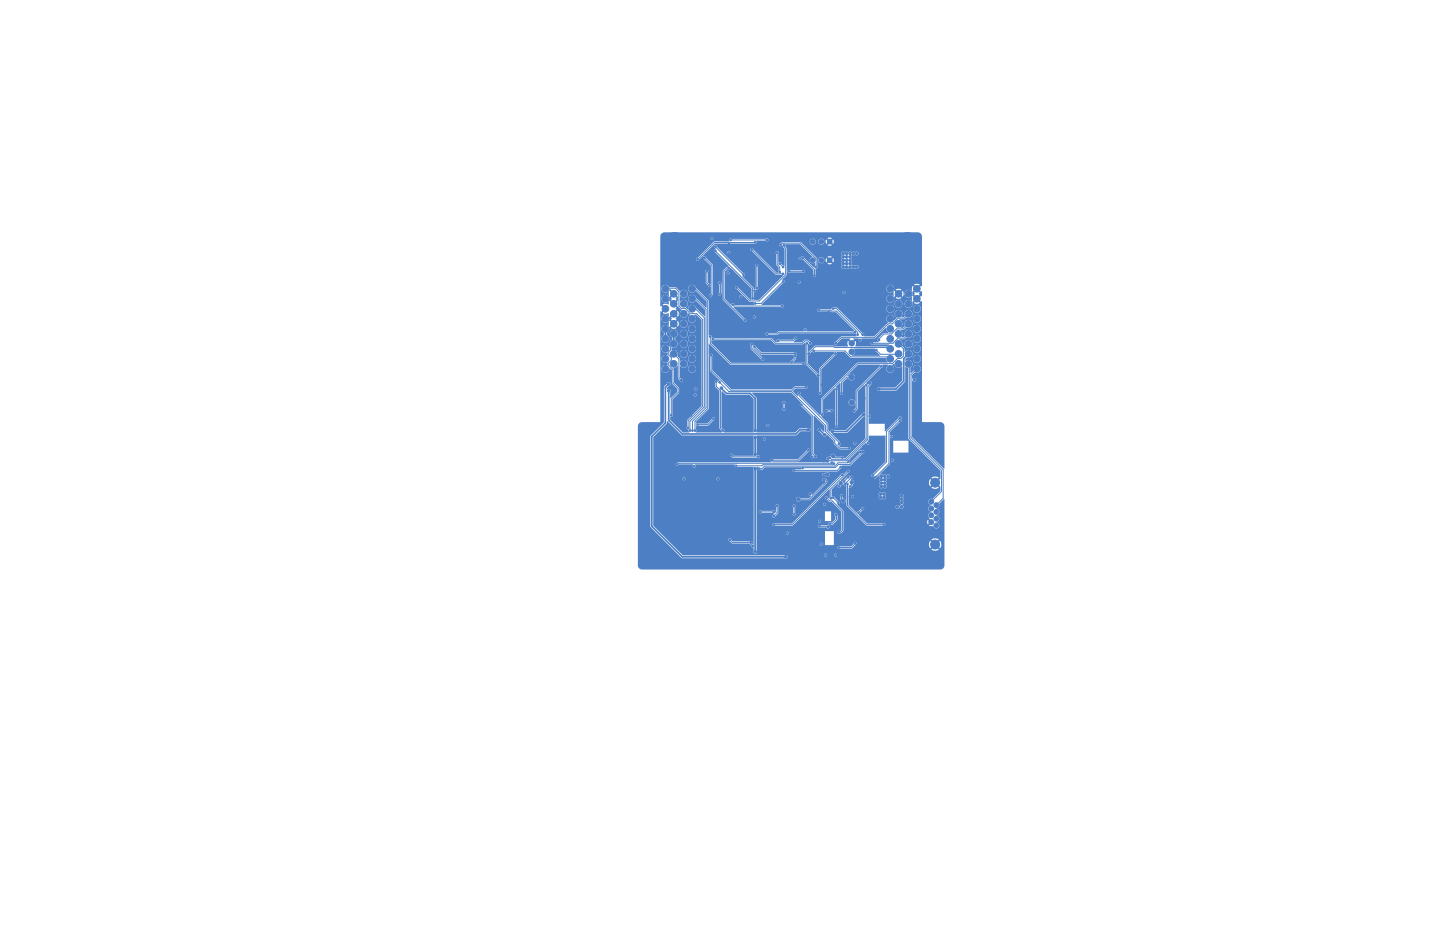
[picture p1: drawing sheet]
<svg xmlns="http://www.w3.org/2000/svg" width="432mm" height="279mm" viewBox="0 0 432 279" stroke-linecap="round" stroke-linejoin="round" font-family="sans-serif">
<g fill="#4d7fc4" stroke="#4d7fc4" stroke-width=".3">
<circle cx="255.4" cy="102.9" r=".8"/>
<circle cx="255.4" cy="105.5" r=".8"/>
<circle cx="255.4" cy="113.1" r=".8"/>
<circle cx="255.4" cy="120.7" r=".8"/>
<circle cx="202.3" cy="72.9" r="3.2"/>
<circle cx="278.5" cy="130.1" r="3.2"/>
<circle cx="196" cy="165.7" r="3.2"/>
<circle cx="207.5" cy="86.6" r="1"/>
<circle cx="207.5" cy="89.6" r="1"/>
<circle cx="207.5" cy="92.6" r="1"/>
<circle cx="207.5" cy="95.6" r="1"/>
<circle cx="207.5" cy="98.6" r="1"/>
<circle cx="207.5" cy="101.6" r="1"/>
<circle cx="207.5" cy="104.6" r="1"/>
<circle cx="207.5" cy="107.6" r="1"/>
<circle cx="207.5" cy="110.6" r="1"/>
<circle cx="205" cy="88.1" r="1"/>
<circle cx="205" cy="91.1" r="1"/>
<circle cx="205" cy="94.1" r="1"/>
<circle cx="205" cy="97.1" r="1"/>
<circle cx="205" cy="100.1" r="1"/>
<circle cx="205" cy="103.1" r="1"/>
<circle cx="205" cy="106.1" r="1"/>
<circle cx="205" cy="109.1" r="1"/>
<circle cx="202" cy="88.1" r="1"/>
<circle cx="202" cy="91.1" r="1"/>
<circle cx="202" cy="94.1" r="1"/>
<circle cx="202" cy="97.1" r="1"/>
<circle cx="202" cy="100.1" r="1"/>
<circle cx="202" cy="103.1" r="1"/>
<circle cx="202" cy="106.1" r="1"/>
<circle cx="202" cy="109.1" r="1"/>
<circle cx="199.5" cy="86.6" r="1"/>
<circle cx="199.5" cy="89.6" r="1"/>
<circle cx="199.5" cy="92.6" r="1"/>
<circle cx="199.5" cy="95.6" r="1"/>
<circle cx="199.5" cy="98.6" r="1"/>
<circle cx="199.5" cy="101.6" r="1"/>
<circle cx="199.5" cy="104.6" r="1"/>
<circle cx="199.5" cy="107.6" r="1"/>
<circle cx="199.5" cy="110.6" r="1"/>
<circle cx="243.7" cy="78" r=".72"/>
<circle cx="246.3" cy="78" r=".72"/>
<circle cx="248.8" cy="78" r=".72"/>
<circle cx="266.9" cy="110.6" r="1"/>
<circle cx="266.9" cy="107.6" r="1"/>
<circle cx="266.9" cy="104.6" r="1"/>
<circle cx="266.9" cy="101.6" r="1"/>
<circle cx="266.9" cy="98.6" r="1"/>
<circle cx="266.9" cy="95.6" r="1"/>
<circle cx="266.9" cy="92.6" r="1"/>
<circle cx="266.9" cy="89.6" r="1"/>
<circle cx="266.9" cy="86.6" r="1"/>
<circle cx="269.4" cy="109.1" r="1"/>
<circle cx="269.4" cy="106.1" r="1"/>
<circle cx="269.4" cy="103.1" r="1"/>
<circle cx="269.4" cy="100.1" r="1"/>
<circle cx="269.4" cy="97.1" r="1"/>
<circle cx="269.4" cy="94.1" r="1"/>
<circle cx="269.4" cy="91.1" r="1"/>
<circle cx="269.4" cy="88.1" r="1"/>
<circle cx="272.4" cy="109.1" r="1"/>
<circle cx="272.4" cy="106.1" r="1"/>
<circle cx="272.4" cy="103.1" r="1"/>
<circle cx="272.4" cy="100.1" r="1"/>
<circle cx="272.4" cy="97.1" r="1"/>
<circle cx="272.4" cy="94.1" r="1"/>
<circle cx="272.4" cy="91.1" r="1"/>
<circle cx="272.4" cy="88.1" r="1"/>
<circle cx="274.9" cy="110.6" r="1"/>
<circle cx="274.9" cy="107.6" r="1"/>
<circle cx="274.9" cy="104.6" r="1"/>
<circle cx="274.9" cy="101.6" r="1"/>
<circle cx="274.9" cy="98.6" r="1"/>
<circle cx="274.9" cy="95.6" r="1"/>
<circle cx="274.9" cy="92.6" r="1"/>
<circle cx="274.9" cy="89.6" r="1"/>
<circle cx="274.9" cy="86.6" r="1"/>
<circle cx="272.2" cy="72.9" r="3.2"/>
<circle cx="243.7" cy="72.4" r=".72"/>
<circle cx="246.3" cy="72.4" r=".72"/>
<circle cx="248.8" cy="72.4" r=".72"/>
<circle cx="280.8" cy="151.4" r=".72"/>
<circle cx="279.2" cy="150.4" r=".72"/>
<circle cx="279.2" cy="152.4" r=".72"/>
<circle cx="279.2" cy="154.5" r=".72"/>
<circle cx="280.8" cy="153.5" r=".72"/>
<circle cx="280.8" cy="155.5" r=".72"/>
<circle cx="280.8" cy="157.5" r=".72"/>
<circle cx="279.2" cy="156.5" r=".72"/>
<circle cx="280.4" cy="163.2" r="1.35"/>
<circle cx="280.4" cy="144.7" r="1.35"/>
<circle cx="252.9" cy="150.2" r=".5"/>
<circle cx="252.1" cy="144.8" r=".5"/>
<circle cx="248" cy="142.3" r=".5"/>
<circle cx="255.4" cy="144.6" r=".5"/>
<circle cx="249.8" cy="136.7" r=".5"/>
<circle cx="239.4" cy="149.7" r=".5"/>
<circle cx="232" cy="158.5" r=".25"/>
<circle cx="264.8" cy="135.4" r=".25"/>
<circle cx="229.2" cy="135.4" r=".25"/>
<circle cx="219.1" cy="134.2" r=".25"/>
<circle cx="257.9" cy="88.9" r=".25"/>
<circle cx="218.6" cy="73.3" r=".25"/>
<circle cx="233.8" cy="88.9" r=".25"/>
<circle cx="220.1" cy="78.3" r=".25"/>
<circle cx="263" cy="74.5" r=".38"/>
<circle cx="214.2" cy="141.5" r=".25"/>
<circle cx="253.6" cy="161.6" r=".25"/>
<circle cx="251.6" cy="100.6" r=".25"/>
<circle cx="214.5" cy="77.8" r=".25"/>
<circle cx="264" cy="72.4" r=".38"/>
<circle cx="263" cy="71.4" r=".38"/>
<circle cx="217.8" cy="129.1" r=".25"/>
<circle cx="243.2" cy="98.9" r=".25"/>
<circle cx="263" cy="73.5" r=".38"/>
<circle cx="261" cy="84.1" r=".25"/>
<circle cx="207.4" cy="140.3" r=".25"/>
<circle cx="240.7" cy="145.6" r=".25"/>
<circle cx="217.8" cy="125.5" r=".25"/>
<circle cx="251.6" cy="128.3" r=".25"/>
<circle cx="229.2" cy="94.8" r=".25"/>
<circle cx="264.8" cy="151.9" r=".38"/>
<circle cx="264" cy="71.4" r=".38"/>
<circle cx="224.4" cy="125.5" r=".25"/>
<circle cx="252.3" cy="97.8" r=".25"/>
<circle cx="270.6" cy="81.6" r=".38"/>
<circle cx="271.4" cy="79.8" r=".38"/>
<circle cx="224.4" cy="120.4" r=".25"/>
<circle cx="265" cy="71.4" r=".38"/>
<circle cx="269.4" cy="128.1" r=".25"/>
<circle cx="265.8" cy="151.9" r=".38"/>
<circle cx="247" cy="144.6" r=".25"/>
<circle cx="254.1" cy="133.7" r=".25"/>
<circle cx="245.7" cy="152.2" r=".25"/>
<circle cx="269.9" cy="156.3" r=".25"/>
<circle cx="269.6" cy="81.6" r=".38"/>
<circle cx="265" cy="72.4" r=".38"/>
<circle cx="259.1" cy="119.4" r=".3"/>
<circle cx="242.9" cy="87.7" r=".3"/>
<circle cx="265" cy="133.1" r=".25"/>
<circle cx="257.9" cy="113.3" r=".25"/>
<circle cx="208.2" cy="133.1" r=".25"/>
<circle cx="214" cy="91.5" r=".25"/>
<circle cx="231" cy="83.6" r=".25"/>
<circle cx="227.5" cy="146.1" r=".25"/>
<circle cx="270.9" cy="144.6" r=".38"/>
<circle cx="213" cy="111.8" r=".25"/>
<circle cx="246" cy="109" r=".25"/>
<circle cx="219.1" cy="137.7" r=".25"/>
<circle cx="271.4" cy="80.8" r=".38"/>
<circle cx="206.4" cy="143.6" r=".25"/>
<circle cx="216.8" cy="108.5" r=".25"/>
<circle cx="270.6" cy="78.5" r=".38"/>
<circle cx="235.1" cy="114.9" r=".25"/>
<circle cx="246.3" cy="161.3" r=".25"/>
<circle cx="273.2" cy="136.7" r=".25"/>
<circle cx="245.7" cy="120.7" r=".25"/>
<circle cx="207.1" cy="124.5" r=".25"/>
<circle cx="257.9" cy="96.1" r=".25"/>
<circle cx="260" cy="97.3" r=".25"/>
<circle cx="254.6" cy="165.4" r=".25"/>
<circle cx="247" cy="164.4" r=".25"/>
<circle cx="242.7" cy="166.4" r=".25"/>
<circle cx="231" cy="118.4" r=".25"/>
<circle cx="207.6" cy="161.6" r=".25"/>
<circle cx="249.3" cy="151.2" r=".25"/>
<circle cx="269.6" cy="78.5" r=".38"/>
<circle cx="206.1" cy="80.3" r=".25"/>
<circle cx="235.3" cy="96.8" r=".25"/>
<circle cx="236.1" cy="154.7" r=".25"/>
<circle cx="233" cy="124.8" r=".25"/>
<circle cx="250.1" cy="108.3" r=".25"/>
<circle cx="224.4" cy="123" r=".25"/>
<circle cx="253.1" cy="89.7" r=".25"/>
<circle cx="233" cy="104.2" r=".25"/>
<circle cx="210.2" cy="143.6" r=".25"/>
<circle cx="270.9" cy="143.3" r=".38"/>
<circle cx="267.3" cy="124.3" r=".25"/>
<circle cx="252.9" cy="165.4" r=".25"/>
<circle cx="221.1" cy="105.2" r=".25"/>
<circle cx="269.9" cy="144.6" r=".38"/>
<circle cx="233.3" cy="107.2" r=".25"/>
<circle cx="213" cy="116.9" r=".25"/>
<circle cx="269.9" cy="143.3" r=".38"/>
<circle cx="246.5" cy="115.4" r=".25"/>
<circle cx="254.9" cy="148.9" r=".25"/>
<circle cx="239.9" cy="123.2" r=".25"/>
<circle cx="219.8" cy="95.3" r=".25"/>
<circle cx="240.2" cy="131.4" r=".25"/>
<circle cx="211.5" cy="161.6" r=".25"/>
<circle cx="250.8" cy="113.6" r=".25"/>
<circle cx="250.1" cy="125.8" r=".25"/>
<circle cx="242.7" cy="127.8" r=".25"/>
<circle cx="265.8" cy="150.9" r=".38"/>
<circle cx="262.8" cy="158.3" r=".25"/>
<circle cx="246" cy="101.9" r=".25"/>
<circle cx="245.7" cy="133.1" r=".25"/>
<circle cx="217.8" cy="127.6" r=".25"/>
<circle cx="257.9" cy="104.9" r=".25"/>
<circle cx="203.1" cy="135.7" r=".25"/>
<circle cx="229" cy="107" r=".25"/>
<circle cx="220.9" cy="85.1" r=".25"/>
<circle cx="242.2" cy="96.3" r=".25"/>
<circle cx="230" cy="76.5" r=".25"/>
<circle cx="263" cy="72.4" r=".38"/>
<circle cx="269.9" cy="160.1" r=".25"/>
<circle cx="229.7" cy="124.8" r=".25"/>
<circle cx="208.2" cy="119.4" r=".25"/>
<circle cx="247" cy="138.2" r=".25"/>
<circle cx="266.8" cy="151.9" r=".38"/>
<circle cx="230.5" cy="86.4" r=".25"/>
<circle cx="248.1" cy="138.3" r=".25"/>
<circle cx="240.2" cy="75.2" r=".25"/>
<circle cx="248.5" cy="93.6" r=".25"/>
<circle cx="247.3" cy="122.5" r=".25"/>
<circle cx="264.8" cy="150.9" r=".38"/>
<circle cx="219.8" cy="98.3" r=".25"/>
<circle cx="212.7" cy="143.6" r=".25"/>
<circle cx="241.7" cy="157.5" r=".25"/>
<circle cx="262.3" cy="124.5" r=".25"/>
<circle cx="253.1" cy="128.3" r=".25"/>
<circle cx="268.9" cy="143.3" r=".38"/>
<circle cx="259" cy="128.8" r=".3"/>
<circle cx="264" cy="153.2" r=".25"/>
<circle cx="201.8" cy="142.3" r=".25"/>
<circle cx="259.5" cy="137.7" r=".25"/>
<circle cx="209.4" cy="140" r=".25"/>
<circle cx="235.8" cy="145.6" r=".25"/>
<circle cx="238.4" cy="127.3" r=".25"/>
<circle cx="258.2" cy="146.4" r=".25"/>
<circle cx="241.2" cy="165.1" r=".38"/>
<circle cx="217.8" cy="71.9" r=".25"/>
<circle cx="259" cy="133.9" r=".25"/>
<circle cx="256.3" cy="132.9" r=".25"/>
<circle cx="247.5" cy="166.4" r=".25"/>
<circle cx="257.9" cy="135.4" r=".25"/>
<circle cx="243.6" cy="137" r=".25"/>
<circle cx="265.3" cy="143.8" r=".38"/>
<circle cx="267.6" cy="138" r=".25"/>
<circle cx="242.9" cy="148.1" r=".25"/>
<circle cx="264.3" cy="144.8" r=".38"/>
<circle cx="260.2" cy="132.9" r=".25"/>
<circle cx="236.1" cy="159.8" r=".25"/>
<circle cx="265.3" cy="144.8" r=".38"/>
<circle cx="246.3" cy="163.1" r=".25"/>
<circle cx="255.6" cy="148.9" r=".25"/>
<circle cx="247.3" cy="151.2" r=".25"/>
<circle cx="264.3" cy="145.8" r=".38"/>
<circle cx="265.3" cy="142.8" r=".38"/>
<circle cx="250.6" cy="166.4" r=".25"/>
<circle cx="264.3" cy="142.8" r=".38"/>
<circle cx="205.1" cy="143.6" r=".25"/>
<circle cx="245.7" cy="156.3" r=".25"/>
<circle cx="266.3" cy="142.8" r=".38"/>
<circle cx="264.3" cy="143.8" r=".38"/>
<circle cx="265.3" cy="145.8" r=".38"/>
<circle cx="253.9" cy="79" r=".38"/>
<circle cx="252.9" cy="78" r=".38"/>
<circle cx="208.2" cy="139.7" r=".25"/>
<circle cx="267.3" cy="130.9" r=".25"/>
<circle cx="229.2" cy="131.6" r=".25"/>
<circle cx="218.6" cy="75.7" r=".25"/>
<circle cx="252.9" cy="79" r=".38"/>
<circle cx="252.9" cy="77" r=".38"/>
<circle cx="270.4" cy="151.9" r=".38"/>
<circle cx="226.2" cy="87.2" r=".25"/>
<circle cx="256.9" cy="76" r=".38"/>
<circle cx="241.4" cy="98.9" r=".25"/>
<circle cx="253.9" cy="80.1" r=".38"/>
<circle cx="253.1" cy="87.7" r=".25"/>
<circle cx="230.2" cy="127.6" r=".25"/>
<circle cx="264" cy="148.1" r=".38"/>
<circle cx="265" cy="148.1" r=".38"/>
<circle cx="253.9" cy="77" r=".38"/>
<circle cx="253.9" cy="78" r=".38"/>
<circle cx="253.9" cy="76" r=".38"/>
<circle cx="239.9" cy="77.5" r=".25"/>
<circle cx="226.2" cy="95" r=".25"/>
<circle cx="208.4" cy="118.4" r=".25"/>
<circle cx="252.9" cy="76" r=".38"/>
<circle cx="255.9" cy="76" r=".38"/>
<circle cx="255.9" cy="80.1" r=".38"/>
<circle cx="265" cy="149.1" r=".38"/>
<circle cx="256.9" cy="80.1" r=".38"/>
<circle cx="213.5" cy="71.4" r=".25"/>
<circle cx="269.1" cy="151.9" r=".38"/>
<circle cx="264" cy="149.1" r=".38"/>
<circle cx="254.9" cy="79" r=".38"/>
<circle cx="270.4" cy="150.7" r=".38"/>
<circle cx="208.7" cy="116.6" r=".25"/>
<circle cx="254.9" cy="80.1" r=".38"/>
<circle cx="222.1" cy="88.9" r=".25"/>
<circle cx="254.9" cy="76" r=".38"/>
<circle cx="270.4" cy="148.6" r=".38"/>
<circle cx="254.9" cy="78" r=".38"/>
<circle cx="257.9" cy="101.9" r=".25"/>
<circle cx="270.4" cy="149.7" r=".38"/>
<circle cx="252.9" cy="80.1" r=".38"/>
<circle cx="260.8" cy="124.8" r=".25"/>
<circle cx="215.3" cy="143.6" r=".25"/>
<circle cx="239.6" cy="84.6" r=".25"/>
<circle cx="218.3" cy="81.8" r=".25"/>
<circle cx="254.9" cy="77" r=".38"/>
<circle cx="219.7" cy="91.3" r=".25"/>
<circle cx="234.6" cy="91.7" r=".25"/>
<circle cx="226.4" cy="140.5" r=".38"/>
<circle cx="226.4" cy="129.1" r=".38"/>
<circle cx="216.3" cy="116.4" r=".38"/>
<circle cx="226.4" cy="131.1" r=".38"/>
<circle cx="274.2" cy="113.8" r=".38"/>
<circle cx="226.4" cy="136.2" r=".38"/>
<circle cx="226.4" cy="165.4" r=".38"/>
<circle cx="215.8" cy="114.6" r=".25"/>
<circle cx="254.6" cy="134.4" r=".25"/>
<circle cx="206.9" cy="129.1" r=".25"/>
<circle cx="208.4" cy="129.1" r=".25"/>
<circle cx="207.6" cy="129.1" r=".25"/>
<circle cx="201.3" cy="124.5" r=".25"/>
<circle cx="239.6" cy="117.9" r=".25"/>
<circle cx="251.6" cy="133.1" r=".25"/>
<circle cx="246.5" cy="124.3" r=".25"/>
<circle cx="263.5" cy="101.9" r=".3"/>
<circle cx="258.7" cy="135.4" r=".3"/>
<circle cx="240.6" cy="140.3" r=".25"/>
<circle cx="256.2" cy="123.2" r=".25"/>
<circle cx="264.3" cy="109.8" r=".25"/>
<circle cx="261.5" cy="102.9" r=".25"/>
<circle cx="265" cy="157.3" r=".25"/>
<circle cx="254.1" cy="145.1" r=".25"/>
<circle cx="250.6" cy="106" r=".25"/>
<circle cx="250.6" cy="102.9" r=".25"/>
<circle cx="245.9" cy="117.9" r=".25"/>
<circle cx="223.4" cy="96.1" r=".25"/>
<circle cx="218.6" cy="80.3" r=".25"/>
<circle cx="226.2" cy="103.9" r=".25"/>
<circle cx="242.5" cy="106" r=".25"/>
<circle cx="238.4" cy="106" r=".25"/>
<circle cx="250.8" cy="127.8" r=".25"/>
<circle cx="250.8" cy="116.6" r=".25"/>
<circle cx="238.1" cy="141" r=".25"/>
<circle cx="252.1" cy="140" r=".25"/>
<circle cx="233" cy="151.6" r=".25"/>
<circle cx="232" cy="154.7" r=".25"/>
<circle cx="249.6" cy="129.3" r=".38"/>
<circle cx="242.4" cy="128.8" r=".38"/>
<circle cx="247.3" cy="130.4" r=".38"/>
<circle cx="245.7" cy="128.8" r=".38"/>
<circle cx="259" cy="124.3" r=".38"/>
<circle cx="200.5" cy="117.1" r=".38"/>
<circle cx="252.3" cy="117.9" r=".25"/>
<circle cx="263.5" cy="116.6" r=".38"/>
<circle cx="249.5" cy="123.1" r=".25"/>
<circle cx="247.8" cy="123.2" r=".25"/>
<circle cx="204.3" cy="114.1" r=".3"/>
<circle cx="244.7" cy="80.1" r=".25"/>
<circle cx="234.1" cy="73.4" r=".25"/>
<circle cx="212.8" cy="85.6" r=".25"/>
<circle cx="212" cy="81.3" r=".25"/>
<circle cx="211.2" cy="77.3" r=".25"/>
<circle cx="213" cy="88.7" r=".25"/>
<circle cx="231.5" cy="138" r=".25"/>
<circle cx="242.5" cy="134.9" r=".25"/>
<circle cx="220.7" cy="139.6" r=".25"/>
<circle cx="250.1" cy="139" r=".25"/>
<circle cx="258.7" cy="100.3" r=".25"/>
<circle cx="240.7" cy="77.3" r=".25"/>
<circle cx="244.2" cy="82.6" r=".25"/>
<circle cx="249.8" cy="92.5" r=".25"/>
<circle cx="234.8" cy="80.1" r=".25"/>
<circle cx="233.8" cy="79" r=".25"/>
<circle cx="257.2" cy="100.3" r=".25"/>
<circle cx="236.6" cy="81.3" r=".25"/>
<circle cx="240.9" cy="81.3" r=".25"/>
<circle cx="245.5" cy="93" r=".25"/>
<circle cx="235.1" cy="73.5" r=".25"/>
<circle cx="220.9" cy="86.2" r=".25"/>
<circle cx="214.5" cy="75.2" r=".25"/>
<circle cx="225.7" cy="89.5" r=".25"/>
<circle cx="209.2" cy="77.8" r=".25"/>
<circle cx="226.4" cy="72.6" r=".25"/>
<circle cx="230" cy="71.9" r=".25"/>
<circle cx="219.1" cy="71.9" r=".25"/>
<circle cx="222.9" cy="82.3" r=".25"/>
<circle cx="214.5" cy="74" r=".25"/>
<circle cx="203.1" cy="139.2" r=".25"/>
<circle cx="249.4" cy="138.7" r=".25"/>
<circle cx="228.7" cy="107.7" r=".25"/>
<circle cx="225.4" cy="103.2" r=".25"/>
<circle cx="225.2" cy="162.6" r=".25"/>
<circle cx="218.8" cy="161.8" r=".25"/>
<circle cx="258.7" cy="152.4" r=".25"/>
<circle cx="225.7" cy="163.6" r=".25"/>
<circle cx="257.4" cy="153.7" r=".25"/>
<circle cx="232" cy="157.3" r=".25"/>
<circle cx="252.5" cy="142.3" r=".25"/>
<circle cx="247.8" cy="149.1" r=".25"/>
<circle cx="251.6" cy="159.6" r=".25"/>
<circle cx="254.4" cy="143" r=".25"/>
<circle cx="253.1" cy="144.3" r=".25"/>
<circle cx="244" cy="105.2" r=".25"/>
<circle cx="232" cy="153.5" r=".25"/>
<circle cx="228" cy="153.5" r=".25"/>
<circle cx="255.4" cy="143" r=".25"/>
<circle cx="253.4" cy="145.1" r=".25"/>
<circle cx="248.3" cy="158" r=".25"/>
<circle cx="245.7" cy="157.8" r=".25"/>
<circle cx="250.6" cy="154.3" r=".25"/>
<circle cx="248.8" cy="157" r=".25"/>
<circle cx="251.3" cy="150.7" r=".25"/>
<circle cx="249.8" cy="149.1" r=".25"/>
<circle cx="249.1" cy="149.4" r=".25"/>
<circle cx="254.4" cy="141.3" r=".25"/>
<circle cx="245.4" cy="112.6" r=".25"/>
<circle cx="238.6" cy="101.4" r=".25"/>
<circle cx="233.3" cy="102.2" r=".25"/>
<circle cx="241.9" cy="102.9" r=".25"/>
<circle cx="248.8" cy="137.2" r=".25"/>
<circle cx="259.7" cy="115.4" r=".25"/>
<circle cx="226.4" cy="91" r=".25"/>
<circle cx="234.8" cy="84.4" r=".25"/>
<circle cx="226.9" cy="86.4" r=".25"/>
<circle cx="226.9" cy="79.5" r=".25"/>
<circle cx="261" cy="114.9" r=".25"/>
<circle cx="248.1" cy="137.5" r=".25"/>
<circle cx="233.8" cy="81.5" r=".25"/>
<circle cx="233" cy="75.7" r=".25"/>
<circle cx="214.8" cy="114.3" r=".25"/>
<circle cx="216.8" cy="129.1" r=".25"/>
<circle cx="254.4" cy="138.3" r=".25"/>
<circle cx="227.7" cy="140.5" r=".25"/>
<circle cx="251.6" cy="164.1" r=".25"/>
<circle cx="256.4" cy="162.9" r=".25"/>
<circle cx="225.4" cy="74.7" r=".25"/>
<circle cx="234.8" cy="82.1" r=".25"/>
<circle cx="214" cy="125.5" r=".25"/>
<circle cx="209.2" cy="127.3" r=".25"/>
<circle cx="230" cy="100.1" r=".25"/>
<circle cx="256.4" cy="99.6" r=".25"/>
<circle cx="262.8" cy="104.9" r=".25"/>
<circle cx="240.3" cy="121.3" r=".25"/>
<circle cx="244.5" cy="136.9" r=".25"/>
<circle cx="235.1" cy="122.7" r=".25"/>
<circle cx="235.1" cy="120.7" r=".25"/>
<circle cx="261.7" cy="142.5" r=".25"/>
<circle cx="269.9" cy="125.3" r=".25"/>
<circle cx="262.5" cy="143" r=".25"/>
<circle cx="269.9" cy="126.1" r=".25"/>
<circle cx="240.9" cy="109" r=".25"/>
<circle cx="213" cy="100.9" r=".25"/>
<circle cx="213.2" cy="106.5" r=".25"/>
<circle cx="241.7" cy="116.1" r=".25"/>
<circle cx="242.9" cy="102.9" r=".25"/>
<circle cx="213.7" cy="101.6" r=".25"/>
<circle cx="215.8" cy="88.2" r=".25"/>
<circle cx="215.8" cy="84.8" r=".25"/>
<circle cx="238.1" cy="154.2" r=".25"/>
<circle cx="238.1" cy="151.7" r=".25"/>
<circle cx="200.5" cy="115.1" r=".38"/>
<circle cx="235.6" cy="166.9" r=".38"/>
<circle cx="227.5" cy="137" r=".25"/>
<circle cx="219.3" cy="136.4" r=".25"/>
<circle cx="206.3" cy="128.3" r=".25"/>
<circle cx="251.6" cy="145.8" r=".25"/>
<circle cx="252.3" cy="148.6" r=".25"/>
<circle cx="254.9" cy="145.8" r=".25"/>
<circle cx="247" cy="142.3" r=".25"/>
<circle cx="247" cy="143.8" r=".3"/>
<circle cx="252.6" cy="137.1" r=".25"/>
<circle cx="238.4" cy="106.7" r=".25"/>
<circle cx="237.4" cy="108.5" r=".25"/>
</g>
<g fill="none" stroke="#4d7fc4" stroke-width=".3">
<path d="M211.2 77.3l2.3 2.3v8.6l-.5 .5M214.5 75.2l11.2 11.2v3.1M214.5 74l8.4 8.3M219.1 71.9h10.9M225.4 74.7l7.3 7.4h2.1M226.4 72.6l-12.2 .1-5 5.1M226.9 79.6v6.8M233 75.7v3.6l.8 .8v1.4M233.8 79l1 1.1M234.1 73.4l.5-.5h5.4l4.7 4.7v2.4M235.1 73.5v.5l.5 .5v7.8l-7.9 7.9h-2.8l-4-4M240.7 77.3l3.5 3.5v1.8"/>
<path d="M199.7 86.4h2.9l1 1v4.3l.7 .8h1.2l1.5 1.5h1.9l1.8 1.8v25.9l-4.4 4.4v2.2M207.5 92.6h1l2.7 2.6v26.8l-4.3 4.3v2.8M207.5 86.6h1l3.7 3.6v32.3l-3.8 3.8v2.8M207.5 89.6h1l3.2 3.1v29.5l-4.1 4.1v2.8M212 81.3v3.5l.8 .8M212.8 85.6h.1M215.8 84.8l.2 .3v2.8l-.2 .3M218.6 80.3h-.5l-1.1 1v8.4l6.4 6.4M219.7 91.3l.4 .4h14.5M234.8 84.4l-6.6 6.6h-1.8M236.6 81.3h4.3M244.7 80v.1"/>
<path d="M245.5 93h3.6l.2 .3h1.5l6.4 6.3v.7M249.8 92.5h1.1l7.8 7.8M256.4 99.6h-22.8l-.6 .5h-3M257.9 99.6h.1M272.4 97.1l-1.5 1.5h-2.1l-1.5 1.5h-2.3l-1.5 1.5v.3M272.4 94.1l-1.3 1.3h-1.8l-1.7 1.7h-1.3l-4 4h-10l-1.7 1.8M202 103.1l-1 1v.9l-.5 .5v.9l.8 .8v.8l-.8 .7v.8l1.3 1.3v4.1l1.5 1.5v1.3l-2 2v4.8M202 106.1l1.6 1.5v5.7l.7 .8M213 100.9v2l6.1 6.2 21.8-.1M213.2 106.5v4.5l5.9 6h18.5l.9-.9h3.2M213.7 101.6h17.6l1.2 1.3h8.1l.8-.7h.8l.7 .7M214.8 114.3v1.5l1.2 1.3v11.2l.8 .8"/>
<path d="M215.8 114.6l2.8 2.8h18.8l10.1 10.2v1.7l2.8 2.8v.8l1.5 1.5h2.8M225.4 103.2v1.2l3.3 3.3M226.2 103.9l2 2.1h10.2M238.4 106.7v.8l-1 1M238.6 101.4l-.7 .8h-4.6M239.6 117.9v.7l8.4 8.4v2.1l3.6 3.5v.5M241.9 102.9v6.2l3.5 3.5M244 105.2h9.4l1.7 1.8h11.2M250.6 106l-4.7 4.6v7.3M250.8 116.6v11.2M255.4 113.1h-1.5l-1.6 1.5v3.3M259.7 115.4v16.2l-6.1 6.1h-4.3l-.5-.5"/>
<path d="M261 114.9v.2l-.8 .8v15.8l-6.4 6.4h-5l-.7-.6M262.8 105l1.2 1.2h5.3M264.3 109.8l-7.4 7.3v5.4l-.7 .7M266.5 104.2h-16.2l-.3-.3h-5.6l-1.9 2.1M269.4 103.1l1.5 1.4v2.2l-.8 .8h-1l-1.5 1.5h-10.4l-10.7 10.7v4.6M272.4 100.1l-1.3 1.3h-1.8l-1.6 1.5h-6.2M272.7 109.3v22.1l9.6 9.6v6.3l-3.1 3.1M274.9 110.6l-1.7 1.7v18.8l9.6 9.7v8.6l-2 2M214 125.5l-1.8 1.8h-3M219.3 136.4l.5 .6h7.7M221.1 138.9h.1M235.1 120.7v2"/>
<path d="M240.3 121.3l3.4 3.5v11.3l.8 .8M242.4 134.9l-3 3.1h-7.9M242.4 134.9h.1M249.4 138.7l-.2 .2h-45.8l-.3 .3M249.5 123.1l-1.7 .1M249.8 136.7l.5 .5 2.3-.1M250.1 139l-.3 .3h-21l-.4 .3h-7.7M251.6 132.7h.1M254.4 138.3l-.3 .4h-2.8l-1 1h-21.1l-.7 .8h-.8M258.7 135.5l-3.8 3.7h-3.5l-.9 1-9.9 .1M258.7 135.4v.1M269.9 125.3l-4.1 4v9.2l-4.1 4"/>
<path d="M269.9 126.1l-3.3 3.3v9.6l-4.1 4.1M228 153.5h4M233 151.6v2.1l-1 1M238.1 151.7v2.5M245.7 157.8h2.3l.3 .2M247 142.3h1M247 143.8h.5l.3 .3v.5l-5.1 5.1h-3.3M247.8 149.1l1 1.1h.8l3 3v5.9l-.5 .5h-.5M249.8 149.1l1.5 1.6M250.6 154.3l.2 .3v1.2l-1.2 1.2h-.8M252.1 140l-1 1h-13M252.1 144.8l-.5 .5v.5"/>
<path d="M252.3 148.6v1.1l.6 .5M252.5 142.3h.1M252.5 142.3l-14.9 15h-5.6M254.1 145.1v6.3l5.9 5.9h5M254.4 143.1l-1.3 1.2M254.4 141.3l-5.3 5.2v2.9M255.4 143.1l-2 2M255.4 144.6v.7l-.5 .5M258.7 152.4l-1.3 1.3M218.8 161.8l.8 .8h5.5M225.2 162.6h-.1M225.2 162.6v.5l.5 .5"/>
<path d="M252.4 164.1h.1M252.8 164.1h.1M256.4 162.9v.2l-1.1 1h-3.7"/>
</g>
<path d="M199.5 98.9v3M200.5 115.1l-1 1v10.7l-4 4.1v26.9l9.1 9.1h31M200.5 117.1v8.9l4.1 4.1h34l1.3-1.3h2.5M202 100.1v3M216.3 116.4l1.6 1.6h7.1l1.4 1.4v9.7M272.4 106.1l-1.4 1.4v6.7l-2.4 2.4h-5.1M226.4 131.1v5.1M245.7 128.8l1.6 1.6M259 124.3l-5.1 5h-4.3M226.4 140.5v24.9" fill="none" stroke="#4d7fc4" stroke-width=".51"/>
<g fill="#4d7fc4">
<path d="M198 93.3l.3 .1 .6-.5 .4 .3-.6 .6 .7 .3 1.1-.2 .1 1a1.25 1.25 0 0 0-1.9-.2 1.25 1.25 0 0 0 .1 1.9 1.25 1.25 0 0 0 1.8-.3l-.1 1.6a1.22 1.22 0 0 0-1.9 0 1.22 1.22 0 0 0 .5 1.8v.8a1.22 1.22 0 0 0-.4 1.9 1.22 1.22 0 0 0 2-.2 1.22 1.22 0 0 0-.8-1.8l.1-.7a1.73 1.73 0 0 0 .7-1.7l.7-.6 .4 .3-.6 .6 .5 .2h4.7a1.18 1.18 0 0 0 1.6 1.2 1.18 1.18 0 0 0 .3-2 1.18 1.18 0 0 0-1.9 .7l-3.8 .1 .3-.2-.6-.6 .4-.3 .6 .5 .2-.9h.4v.2a1.18 1.18 0 0 0 1.8 .9 1.18 1.18 0 0 0 0-2 1.18 1.18 0 0 0-1.8 .9h-.4l-.2-.8-.6 .6-.4-.4 .6-.6-.3-.2 .3-.3-.6-.6 .4-.3 .6 .5a1.49 1.49 0 0 0 0-1.7l-.6 .6-.4-.4 .6-.6-.3-.2 .3-.3-.6-.6 .4-.3 1.8 1.6a1.25 1.25 0 0 0 .1 2.2 1.25 1.25 0 0 0 1.7-1.4l.7 .7a1.18 1.18 0 0 0-.4 1.8 1.18 1.18 0 0 0 1.8 .1 1.18 1.18 0 0 0-.3-1.8l.1-.3 .6 .1 1.6 1.6v25.6l-4.4 4.4-.1 2.4 .6 .4 .1 .9-1.9-.1-3.7-3.7v-1a.48 .48 0 0 0 .6-.1 .48 .48 0 0 0 0-.7v-4.2l1.5-1.5 4.9 .1a.44 .44 0 0 0 .6 .3 .44 .44 0 0 0 0-.8 .44 .44 0 0 0-.6 .4h-4.9l.5-.6v-1.2h4.6a.44 .44 0 0 0 .6 .4 .44 .44 0 0 0 .2-.7 .44 .44 0 0 0-.7 .2l-4.7 .1v-.4l-1.5-1.4v-4l-.2-.5 1.3-.7 .1 3.8 .6 .7a.5 .5 0 0 0 .5 .5 .5 .5 0 0 0 .4-.6 .5 .5 0 0 0-.5-.4l-.4-.4v-2.7h2.5v.2a1.18 1.18 0 0 0 1.8 .9 1.18 1.18 0 0 0 0-2 1.18 1.18 0 0 0-1.8 .9h-2.5l.1-.7a1.24 1.24 0 0 0 1.8 .1 1.24 1.24 0 0 0 0-1.8 1.24 1.24 0 0 0-1.9 .3v-.9h2.5v.2a1.18 1.18 0 0 0 1.8 .9 1.18 1.18 0 0 0 0-2 1.18 1.18 0 0 0-1.8 .9h-2.5l-.8-.8 .1-.7h.7v.2a1.18 1.18 0 0 0 1.8 .9 1.18 1.18 0 0 0 0-2 1.18 1.18 0 0 0-1.8 .9h-.7v-.2a1.45 1.45 0 0 0-1.8-.9l-.1-.4h5.1v.2a1.18 1.18 0 0 0 1.8 .9 1.18 1.18 0 0 0 0-2 1.18 1.18 0 0 0-1.8 .9h-5.1l.1-.4a1.23 1.23 0 0 0 1.8-1.1h.7v.2a1.18 1.18 0 0 0 1.8 .9 1.18 1.18 0 0 0 0-2 1.18 1.18 0 0 0-1.8 .9h-.7l-.2-.5-.5-.5v-.5h3.9v.2a1.18 1.18 0 0 0 1.8 .9 1.18 1.18 0 0 0 0-2 1.18 1.18 0 0 0-1.8 .9h-3.9v-.3l.6-.7 .1-.5h.7v.2a1.18 1.18 0 0 0 1.8 .9 1.18 1.18 0 0 0 0-2 1.18 1.18 0 0 0-1.8 .9h-.7v-.2a1.21 1.21 0 0 0-2-.6 1.21 1.21 0 0 0 .4 2.1v.7a1.39 1.39 0 0 0-.7 1.7l-.2 .3a1.25 1.25 0 0 0-1.6-.5 1.25 1.25 0 0 0-.7 1.5 1.44 1.44 0 0 0 1.8 .7v.8a1.25 1.25 0 0 0-1.9 1.2 1.25 1.25 0 0 0 1.9 1v.8a1.22 1.22 0 0 0-1.8 .8 1.22 1.22 0 0 0 1.1 1.5 1.22 1.22 0 0 0 1.3-1.5l.7 .6v4.1l1.5 1.6v.9l-1.9 1.9-.1-1.9a.65 .65 0 0 0-.2-.8 .65 .65 0 0 0-.8 0v-.4l.6-.6a.58 .58 0 0 0 .5-.6 .58 .58 0 0 0-.6-.6 .58 .58 0 0 0-.6 .6l-.8 1v10.5l-4.1 4.2 .1 27.2 9.4 9.4h30.7a.58 .58 0 0 0 .8-.1 .58 .58 0 0 0 0-.8 .58 .58 0 0 0-.8 0l-30.6-.1h42.5l.4 .5 .4-.2 .1-.3 2.1 .1a.44 .44 0 0 0 .7 .3 .44 .44 0 0 0 0-.7 .44 .44 0 0 0-.7 .3h-2.1l-.4-.4-.5 .4h-42.5l-8.7-8.8v-14.1h8.8l.3 .5 .4-.1 .1-.4h9.3a.44 .44 0 0 0 .6 .5 .44 .44 0 0 0 .2-.7 .44 .44 0 0 0-.7 .1l-9.4 .1-.5-.4-.3 .4h-8.8v-12.5l4-3.9 .2-.9 4.4 4.3h21.5l-.1 6.1h-6a.51 .51 0 0 0-.5-.5 .51 .51 0 0 0-.5 .5l.9 .7h7.4a.45 .45 0 0 0 .6-.1 .45 .45 0 0 0-.1-.7 .45 .45 0 0 0-.7 .1l-.1-5 1.9 .1a.44 .44 0 0 0 .7 .3 .44 .44 0 0 0 0-.7 .44 .44 0 0 0-.7 .3h-1.9l-.1-1 11.9-.1 1.4-1.2h1.9a.61 .61 0 0 0 .8-.2 .61 .61 0 0 0-.1-.8 .61 .61 0 0 0-.8 .1h-2.2l-1.3 1.3-11.6-.1 .2-.4-.1-1.7h2.9a.44 .44 0 0 0 .6 .5 .44 .44 0 0 0 .2-.7 .44 .44 0 0 0-.8 .1l-2.9 .1v-6.9h7.7l.1 1.8a.45 .45 0 0 0 .1 .6 .45 .45 0 0 0 .6-.1 .45 .45 0 0 0 0-.6v-1.3a.44 .44 0 0 0-.1-.7 .44 .44 0 0 0-.7 .3h-7.7l-.1-1.3-1.3-1.5 11.7-.1 3.1 3.1a.49 .49 0 0 0-.5 .5 .49 .49 0 0 0 .5 .5l3.1 3.1 .2 11.5a.51 .51 0 0 0-.4 .8 .51 .51 0 0 0 .9-.1 .46 .46 0 0 0 .8 0 .46 .46 0 0 0-.4-.7l-.5-.5 .1-11.2 3.1 3v1.7l-.9-.6a.58 .58 0 0 0-.6-.5 .58 .58 0 0 0-.5 .5 .58 .58 0 0 0 .5 .6l1 1a.64 .64 0 0 0 .7 .5 .64 .64 0 0 0 .6-.6l2 1.9 .1 .9 1.6 1.6h2.6a.45 .45 0 0 0 .7 0 .45 .45 0 0 0-.1-.7 .45 .45 0 0 0-.6 .1h-2.3l-.4-.5 .4-.3-.1-.5h4a.44 .44 0 0 0 .6 .5 .44 .44 0 0 0 .2-.7 .44 .44 0 0 0-.8 .1l-4 .1-.1-.4-2.3-2.4 .5-.2 4-.1 5-4.9 .3-.1 .1 6.8-5.8 5.8-.4 .1a.57 .57 0 0 0-.3-.6 .57 .57 0 0 0-.7 .1h-1.7a.78 .78 0 0 0-.7-.9 .78 .78 0 0 0-.8 .8l-.6 .2a.49 .49 0 0 0-.7 .3 .49 .49 0 0 0 .5 .6l.4 .7-16.9-.1 .2-.2h7.6l2.9-2.9a.44 .44 0 0 0 .5-.4 .44 .44 0 0 0-.4-.5 .44 .44 0 0 0-.5 .4l-2.8 2.8-7.4-.1a.5 .5 0 0 0-.7 .2 .5 .5 0 0 0 .2 .7l-27.9 .1a.56 .56 0 0 0-.6 .4 .56 .56 0 0 0 .3 .7l.5-.5h4.3a.53 .53 0 0 0-.1 .7 .53 .53 0 0 0 .6 .2l.1-.9 11.8 .1a.49 .49 0 0 0 .1 .6 .49 .49 0 0 0 .6 0l5 .1v23.2l-.5-.2a.51 .51 0 0 0 0-.7 .51 .51 0 0 0-.7 0h-5l-.5-.4a.46 .46 0 0 0-.5-.5 .46 .46 0 0 0-.4 .5 .46 .46 0 0 0 .5 .4l.6 .6h5.3l.6 1.1 .6 .1v1a.57 .57 0 0 0 .1 .7 .57 .57 0 0 0 .8 0 .57 .57 0 0 0 0-.8v-.9h24.3l.3 .5 3.9-.2 1.3-1.3h21.9l.3 1.3 .6-.6 .4 .3-.5 .7a1.85 1.85 0 0 0 2.1-.1l-.6-.6 .4-.3 .7 .5a1.85 1.85 0 0 0-.1-2.2l-.6 .6-.4-.4 .5-.6a1.85 1.85 0 0 0-2.1 .1l.6 .5-.4 .4-.6-.6-.3 1-21.8-.1a.46 .46 0 0 0-.5-.6 .46 .46 0 0 0-.4 .7l-.7 .7-3.7-.1-.3 .4h-24.3v-1h18.9a.44 .44 0 0 0 .6 .5 .44 .44 0 0 0 .2-.7 .44 .44 0 0 0-.8 .1l-18.9 .1v-3.3h8.8a.44 .44 0 0 0 .5 .4 .44 .44 0 0 0 .2-.7 .44 .44 0 0 0-.7 .1l-8.8 .2v-.6h20.5v4.2h2.6v-4.2h-23.1v-1.5h18.4l.4 .5 2.1-.1a.48 .48 0 0 0 .6 .3 .48 .48 0 0 0 .3-.6 .48 .48 0 0 0-.6-.3l-2.4-.2-.4 .4h-18.4v-.5h4.7a.48 .48 0 0 0 .3 .4 .48 .48 0 0 0 .5 0h5.2l.7-.6h10.1l.1 .4 .3 .1 .9-.2 1.4-1.4v-1.5a.5 .5 0 0 0-.4-.5 .5 .5 0 0 0-.6 .3 .5 .5 0 0 0 .4 .6v.8l-1 1.1-.8-.1-.3 .4h-10.1l.8-.8 6.2 .1a.44 .44 0 0 0 .7 .3 .44 .44 0 0 0 0-.7 .44 .44 0 0 0-.7 .3h-6.2l2.9-2.9h5.4v2.9h1.8v-2.9h-7.2l2.2-2.2 2.6 .1a.44 .44 0 0 0 .7 .3 .44 .44 0 0 0 0-.7 .44 .44 0 0 0-.7 .3h-2.6l4.6-4.5v2.4l-.2 .5-.4-.4a.45 .45 0 0 0-.5-.4 .45 .45 0 0 0-.4 .5 .45 .45 0 0 0 .5 .4l.9 .8 .8 .1 2.8 2.9v5.5l-.3 .3a.46 .46 0 0 0-.7 0 .46 .46 0 0 0 0 .7 .46 .46 0 0 0 .6 0l.4-.1 .6-.7v-5.9l-1.8-2a.5 .5 0 0 0 .6-.4 .5 .5 0 0 0-.4-.6l-1.2-1.4-.7-.2h2.5l.3 1.3a.68 .68 0 0 0 .4 .9 .68 .68 0 0 0 .9-.6 .68 .68 0 0 0-.7-.7l-.1-.6a.44 .44 0 0 0-.2-.7 .44 .44 0 0 0-.6 .4h-2.5l.1-2 1.8-1.8 .1 .2-.1 .2a.56 .56 0 0 0-.1 .7 .56 .56 0 0 0 .7 .3l.1-.7 .8-.4a.73 .73 0 0 0 1 .4l.1 6.1 5.9 6h5a.45 .45 0 0 0 .6-.1 .45 .45 0 0 0-.1-.6 .45 .45 0 0 0-.6 .1l-4.6-.1-2.7-2.6 1.3-1.4a.45 .45 0 0 0 .4-.5 .45 .45 0 0 0-.5-.4 .45 .45 0 0 0-.4 .5l-1.4 1.2-1.7-1.7h13.5l.4 .5 .7-.4 .2 .2a.62 .62 0 0 0 1-.2 .62 .62 0 0 0-.4-.9l.4-.5-.2-.5 .2-.6-.2-.4a.61 .61 0 0 0 .1-.9 .61 .61 0 0 0-.9 0 .61 .61 0 0 0 .1 .9l-.2 .4 .2 .5a.88 .88 0 0 0 .2 1.3l-.4 .4a.63 .63 0 0 0-.7-.4 .63 .63 0 0 0-.5 .5v.1h-13.5l-.7-.7v-2.5h.8a.44 .44 0 0 0 .6 .5 .44 .44 0 0 0 .2-.7 .44 .44 0 0 0-.8 .1l-.8 .1v-.6h9.1l.2 .4a.65 .65 0 0 0 0 1 .65 .65 0 0 0 .9-.1 .63 .63 0 0 0 .9-.1 .63 .63 0 0 0-.1-.9 .63 .63 0 0 0-.1-.8 .63 .63 0 0 0-.9 .1l-.6-.2-.3 .6h-9.1l.1-2a.59 .59 0 0 0 .9-.4l.3-.4a.8 .8 0 0 0 .4-1 .8 .8 0 0 0-.9-.5l.2-.4a.48 .48 0 0 0 .4-.4 .48 .48 0 0 0-.4-.5 .48 .48 0 0 0-.5 .3l-.7-.3-1.6 1.7-.5-.2 2.2-2.4a.46 .46 0 0 0 .5-.4 .46 .46 0 0 0-.4-.5 .46 .46 0 0 0-.5 .5l-.9 .9a.52 .52 0 0 0-.5-.3 .52 .52 0 0 0-.4 .5l-14.6 14.5-5.5-.1-.4 .4h-4.7v-3.8h.6l.4 .5 3.8-.1 .5 .1-.2 .4a.45 .45 0 0 0-.4 .5 .45 .45 0 0 0 .5 .4 .45 .45 0 0 0 .4-.5l.8-.9 .2-2.2h4.2l.1 2.3a.45 .45 0 0 0 .1 .7 .45 .45 0 0 0 .6-.1 .45 .45 0 0 0-.1-.6v-1.9a.44 .44 0 0 0-.1-.7 .44 .44 0 0 0-.6 .3h-4.2a.45 .45 0 0 0-.7-.3 .45 .45 0 0 0-.1 .7l-.1 1.7a.61 .61 0 0 0-.9-.5l-3.8-.2-.4 .4h-.6v-3.8h11.8l.2 .5 .4 .2 .8-.4h2.7l5.2-5.2v-.7l-.6-.5a.51 .51 0 0 0-.7 0 .51 .51 0 0 0 0 .8 .51 .51 0 0 0 .7-.1l.1 .3-4.1 3.9a.48 .48 0 0 0-.4-.7 .48 .48 0 0 0-.5 .6 .48 .48 0 0 0 .7 .3l-.7 .8h-2.4l-.8-.4-.3 .1-.3 .5h-11.8v-7.4h19.7l.2 .5 .5-.1a.7 .7 0 0 0 .9 .4 .7 .7 0 0 0 .4-.9 .7 .7 0 0 0-1-.3l-.2 .2-.6-.1-.2 .3h-19.7v-2.2l.6 .1a.47 .47 0 0 0-.1 .7 .47 .47 0 0 0 .7 0h.5l.8-.7h10.8v.6h-1.8a.45 .45 0 0 0-.6 .1 .45 .45 0 0 0 .1 .6 .45 .45 0 0 0 .6-.1h12.6l1.3-1 .1-.7 2.6-.1 3.6-3.6a.52 .52 0 0 0 .3-.8 .52 .52 0 0 0-.8 0 .5 .5 0 0 0-.7 .2 .5 .5 0 0 0 .2 .7l-2.9 2.9-.3-.1a.63 .63 0 0 0 .1-1.1l5.1-4.9a.48 .48 0 0 0 .4 .5 .48 .48 0 0 0 .6-.5 .48 .48 0 0 0-.6-.4l.4-.6 .1-1.2 4.9 .1v7.7l-3.7 3.7a.47 .47 0 0 0-.5 .6 .47 .47 0 0 0 .7 .3 .47 .47 0 0 0 .5 .5 .47 .47 0 0 0 .5-.5l.8-.7-.1 .6 .2 .4-.2 .6 .2 .4-.2 .6 .2 .4a.65 .65 0 0 0 0 1 .65 .65 0 0 0 1-.1 .63 .63 0 0 0 .9-.1 .63 .63 0 0 0-.1-.9l.2-.3-.3-.6 .3-.4-.3-.6 .2-.2a.61 .61 0 0 0 .9 .1 .61 .61 0 0 0 0-.9 .61 .61 0 0 0-.9 .2l-.4-.3-.6 .3-1-.3 3-3v-1.3l.4 .1a.44 .44 0 0 0 .6 .3 .44 .44 0 0 0 0-.7 .44 .44 0 0 0-.6 .3h-.4v-2.2h5.6v-3.6h-4.6v3.6h-1l.1-4.5a.48 .48 0 0 0 .8-.1 .48 .48 0 0 0-.4-.7l-.4 .1v-1l3-3a.6 .6 0 0 0 .3-1 .45 .45 0 0 0-.2-.7 .45 .45 0 0 0-.6 .5l-4 4-.1-2.3-4.7 .1-.1-1.8a.51 .51 0 0 0 .6-.3 .51 .51 0 0 0-.3-.7l-.3-.1v-8.1l.8-.9a.48 .48 0 0 0 0-.6 .48 .48 0 0 0-.6-.1 .48 .48 0 0 0-.2 .6l-.3 .3-.5-.6 4.9-4.8v-.6h1.8a1.25 1.25 0 0 0-.4 1.9 1.25 1.25 0 0 0 2 0 1.25 1.25 0 0 0-.5-1.9l.7-.4a1.34 1.34 0 0 0 .9 1.2 1.34 1.34 0 0 0 1.4-.4v4.3l-2 2.1h-4.6a.57 .57 0 0 0-.8 .1 .57 .57 0 0 0 0 .8 .57 .57 0 0 0 .8 0l5-.1 2.5-2.6 .1-4.4 .8 .3 .1 21.2 9.6 9.6v2.4l-.7 .7-.4-.4 .6-.6-.3-.2a1.85 1.85 0 0 0-1.9 .2l.6 .6-.4 .4-.6-.5a1.85 1.85 0 0 0 0 2.1l.6-.6 .4 .4-.5 .6a1.85 1.85 0 0 0 2.1 0l-.6-.6 .4-.4 .7 .7v1.3l-2.3 2.3a1 1 0 0 0-1.3 .7 1 1 0 0 0 .8 1.3 1.03 1.03 0 0 0-.8 1 1.03 1.03 0 0 0 .8 1 1.08 1.08 0 0 0-.8 .8 1.08 1.08 0 0 0 .3 1.1l-.1 .1 .6 .6-.4 .4-.6-.7-.1 1.2 .1 .2 .6-.6 .4 .3-.6 .6 1.1 .2a1 1 0 0 0 1.1 .8 1 1 0 0 0 .9-1 1 1 0 0 0-.9-1 1.03 1.03 0 0 0 .9-1 1.03 1.03 0 0 0-.9-1.1 1.03 1.03 0 0 0 .9-1 1.03 1.03 0 0 0-.9-1l.1-.1a1.02 1.02 0 0 0 .7-1.3l1.6-1.3v19.8a1.27 1.27 0 0 1-1.3 1.2h-89.8a1.27 1.27 0 0 1-.8-1.2v-41.9l.3-.7 .7-.3 5.5-.1 .2-.2z"/>
<path d="M217.4 81.4l.7-.7a.74 .74 0 0 0 1.1-.4l6.1 6.2v3.4h-.3l-3.7-3.7a.46 .46 0 0 0-.4-.5 .46 .46 0 0 0-.5 .5 .46 .46 0 0 0 .5 .4l3.8 3.9h1.4v.8l-5.9 .1a.56 .56 0 0 0-.5-.5 .56 .56 0 0 0-.6 .4l-1.7-1.7-.1-.7h4.4a.44 .44 0 0 0 .6 .5 .44 .44 0 0 0 .1-.7 .44 .44 0 0 0-.7 .1l-4.4 .1v-7.1h.6a.44 .44 0 0 0 .5 .5 .44 .44 0 0 0 .2-.8 .44 .44 0 0 0-.7 .2l-.6 .1z"/>
<path d="M198.4 70l.9-.4 76.1 .1 .8 .5 .3 .7v14.8h-.3l-.6 .6-.4-.4 .5-.6a1.5 1.5 0 0 0-1.6 0l.6 .6-.4 .4-.6-.6-.3 .8 .1 .9a1.25 1.25 0 0 0-1.9-.2 1.25 1.25 0 0 0 .1 1.9 1.25 1.25 0 0 0 1.8-.3l-.1 1.6a1.2 1.2 0 0 0-2 .1 1.2 1.2 0 0 0 1.1 1.8 1.2 1.2 0 0 0 1-1.8l.8-.6 .4 .3-.6 .6a1.49 1.49 0 0 0 1.7 0l-.6-.6 .4-.3 .6 .5h.3v35.9l.2 .2 5.4 .1 1 .6v13.3l-9.6-9.5 .1-16.9a.61 .61 0 0 0 .9 .3 .61 .61 0 0 0 .1-1 .61 .61 0 0 0-1 .2l-.1-1.2 .8-.8a1.19 1.19 0 0 0 1.7-1 1.19 1.19 0 0 0-1.5-1.2 1.19 1.19 0 0 0-.7 1.8l-.8 .7v-1.8a1.25 1.25 0 0 0 .3-1.8 1.25 1.25 0 0 0-1.8-.1l.1-.7h2.2v.2a1.18 1.18 0 0 0 1.8 .9 1.18 1.18 0 0 0 0-2 1.18 1.18 0 0 0-1.8 .9h-2.2l.3-.3a1.21 1.21 0 0 0 1.6-.5 1.21 1.21 0 0 0-.4-1.6 1.21 1.21 0 0 0-1.7 .4l-.2-.1v-.9h2.6v.2a1.18 1.18 0 0 0 1.8 .9 1.18 1.18 0 0 0 0-2 1.18 1.18 0 0 0-1.8 .9h-2.6l-.7-.8 .1-.7h.7v.2a1.18 1.18 0 0 0 1.8 .9 1.18 1.18 0 0 0 0-2 1.18 1.18 0 0 0-1.8 .9h-.7l-.3-.7-.6-.5 1.5-.1 .3-.2h2.3v.2a1.18 1.18 0 0 0 1.8 .9 1.18 1.18 0 0 0 0-2 1.18 1.18 0 0 0-1.8 .9h-2.3l.3-.3a1.21 1.21 0 0 0 1.8-.6 1.21 1.21 0 0 0-1-1.6 1.21 1.21 0 0 0-1.3 1.4l.1 .3-.4 .3h-.7a1.52 1.52 0 0 0-.2-2.1h.9l.5-.4h2.3v.2a1.18 1.18 0 0 0 1.8 .9 1.18 1.18 0 0 0 0-2 1.18 1.18 0 0 0-1.8 .9h-2.3l.3-.3a1.21 1.21 0 0 0 1.8-.6 1.21 1.21 0 0 0-1-1.6 1.21 1.21 0 0 0-1.3 1.4l.1 .3-.6 .6h-.7a1.67 1.67 0 0 0 .2-2l-.6-.5 1.5-.1 .3-.2h2.3v.2a1.18 1.18 0 0 0 1.8 .9 1.18 1.18 0 0 0 0-2 1.18 1.18 0 0 0-1.8 .9h-2.3l.3-.3a1.21 1.21 0 0 0 1.8-.6 1.21 1.21 0 0 0-1-1.6 1.21 1.21 0 0 0-1.3 1.4l.1 .3-.4 .3-.7 .1a1.23 1.23 0 0 0-.3-2.1 1.23 1.23 0 0 0-1.7 1.2l.7 1-.8 .8a1.25 1.25 0 0 0-.8-1.5 1.25 1.25 0 0 0-1.6 .6 1.25 1.25 0 0 0 .5 1.6l-4.1 4.1h-3.2a.54 .54 0 0 0-.3-.9l-7.4-7.4h14.5a1.18 1.18 0 0 0 1.1 1.3 1.18 1.18 0 0 0 1.2-1.3h5.7v.2a1.18 1.18 0 0 0 1.8 .9 1.18 1.18 0 0 0 0-2 1.18 1.18 0 0 0-1.8 .9h-5.7v-.2a1.18 1.18 0 0 0-1.3-.9 1.18 1.18 0 0 0-1 1.1h-14.5l-.3-.3-1.2-.1-.5 .6h-3.5a.46 .46 0 0 0-.6 0 .46 .46 0 0 0 0 .6 .46 .46 0 0 0 .6 0h3.1l.4 .3h1.4l5.5 5.6-14.4 .1a.5 .5 0 0 0 0-.7 .5 .5 0 0 0-.7 0 .5 .5 0 0 0 0 .6l-7.6 .1-.6 .5h-2.6a.45 .45 0 0 0-.6 .1 .45 .45 0 0 0 0 .6 .45 .45 0 0 0 .7-.1h2.7l.6-.5 23.1 .1v.8l-4.6 .1-1.6 1.5a.46 .46 0 0 0-.5 .5 .46 .46 0 0 0 .5 .5 .46 .46 0 0 0 .4-.5l1.5-1.5 2.5 .1-.3 .3 .5 .6-.3 .4-.6-.6-.2 .6 .1 1.1-9.8-.3-2 1.9-.2-2.2 .3-.3a.46 .46 0 0 0 .5 .4 .46 .46 0 0 0 .4-.5 .46 .46 0 0 0-.5-.5l-.6-.5h-.9l-.9 .7h-2.4l.5-.7a.46 .46 0 0 0 .5-.5 .46 .46 0 0 0-.5-.4 .46 .46 0 0 0-.4 .4l-.5 .5h-4a.55 .55 0 0 0-.7 0 .55 .55 0 0 0-.1 .7h-.3l-1.3-1.3h-17.8a.6 .6 0 0 0-.2-.6 .6 .6 0 0 0-.7-.1l-.1-10.5-3.8-3.8a1.22 1.22 0 0 0-1.8-.7 1.22 1.22 0 0 0-.2 2 1.22 1.22 0 0 0 2-.4l3.2 3.1v2l-3.2-3a1.22 1.22 0 0 0-1.8-.7 1.22 1.22 0 0 0-.2 2 1.22 1.22 0 0 0 2-.4l2.7 2.6v2l-2.7-2.5a1.29 1.29 0 0 0-1.4-.9 1.29 1.29 0 0 0-1.1 1.4l-.5-.5a1.32 1.32 0 0 0-.4-2.4h-.5l-.9 .5 .1-1.6a1.24 1.24 0 0 0 1.8 .1 1.24 1.24 0 0 0-.1-1.8 1.24 1.24 0 0 0-1.8 .3l-1.2-1.3h-2a1.22 1.22 0 0 0-1.8-.5 1.22 1.22 0 0 0-.2 1.8 1.22 1.22 0 0 0 1.9-.1v1.6a1.25 1.25 0 0 0-1.9-.2 1.25 1.25 0 0 0 .1 1.9 1.25 1.25 0 0 0 1.8-.3l-.1 1-1.1-.2-.7 .2 .6 .6-.4 .4-.6-.6-.3 .1v-14.1h10.7l.2 .4 .3 .1 1-1h.6l.1 .3 2.3 2.2-.1 5.5-.8-.5v-3a.46 .46 0 0 0 0-.7 .46 .46 0 0 0-.7 0 .46 .46 0 0 0 .1 .7v3.2l.8 1.1 .7 .1v2a.53 .53 0 0 0-.6 .4 .53 .53 0 0 0 .4 .6l.8-.9v-3.4h1.5l.4 .5v2.4a.47 .47 0 0 0-.3 .6 .47 .47 0 0 0 .6 .3 .47 .47 0 0 0 .3-.6v-3a.5 .5 0 0 0-.4-.6 .5 .5 0 0 0-.6 .4h-1.5l-.1-5.4-2.2-2.5-.4-.1-.3 .4h-.6l3.3-3.3h.6l.6 .8a.5 .5 0 0 0-.6 .4 .5 .5 0 0 0 .4 .6l4.1 4.1-.7 .3-1.2 1.2 .1 8.5 6.2 6.3a.45 .45 0 0 0 .5 .4 .45 .45 0 0 0 .3-.5 .45 .45 0 0 0-.4-.4l-.7-.6h3.1a.44 .44 0 0 0 .5 .5 .44 .44 0 0 0 .2-.8 .44 .44 0 0 0-.7 .2l-3.1 .1-2.7-2.9h14.3a.45 .45 0 0 0 .6-.1 .45 .45 0 0 0-.1-.6 .45 .45 0 0 0-.6 0l-5.8-.1 .2-.3h39.7a1.18 1.18 0 0 0 1.6 1.2 1.18 1.18 0 0 0 .3-2 1.18 1.18 0 0 0-1.9 .7l-39.7 .1 3.4-3.4 20.7 .1a.44 .44 0 0 0 .6 .3 .44 .44 0 0 0 0-.7 .44 .44 0 0 0-.6 .3h-20.7l1.1-1.1h32.7a1.28 1.28 0 0 0 .8 1.2 1.28 1.28 0 0 0 1.4-.4l-.1 1.6a1.2 1.2 0 0 0-2 .1 1.2 1.2 0 0 0 1.1 1.8 1.2 1.2 0 0 0 1-1.8l.8-.6 .4 .3-.6 .6a1.49 1.49 0 0 0 1.7 0l-.6-.6 .4-.3 .6 .5a1.5 1.5 0 0 0 0-1.7l-.6 .6-.4-.4 .5-.6a1.5 1.5 0 0 0-1.6 0l.6 .6-.4 .4-.8-.7a1.2 1.2 0 0 0-.7-1.7 1.2 1.2 0 0 0-1.5 1.1h-32.7l2.1-1.9h4a.44 .44 0 0 0 .6 .4 .44 .44 0 0 0 .2-.7 .44 .44 0 0 0-.8 .2l-4 .1v-.5l-.6-.3 1.3-1.3v-1.2h.3l.3 .5 4.1-.2a.46 .46 0 0 0 .6 .1 .46 .46 0 0 0 0-.7 .46 .46 0 0 0-.6 0l-4.1-.1-.6 .4v-6.9l-.5-.6 .1-.6h4.4l3.8 3.9a.99 .99 0 0 0-.8 1.3 .99 .99 0 0 0 1.5 .4v.9l-.3 .6-3.2-3.4-.3-.1-.3 .3a.47 .47 0 0 0-.7 0 .47 .47 0 0 0 0 .7 .47 .47 0 0 0 .7-.1h.4l3.2 3.2v1.3a.46 .46 0 0 0 0 .7 .46 .46 0 0 0 .6 0 .46 .46 0 0 0 0-.7v-1.6a.58 .58 0 0 0 .5-.3 .58 .58 0 0 0 0-.6v-1.8h.4a.9 .9 0 0 0 .9 1 .9 .9 0 0 0 .8-1h.5l.2 .8 .6-.6 .4 .3-.7 .7 .6 .2 .8-.2-.7-.7 .4-.3 .6 .6 .2-.6-.2-.7-.6 .6-.4-.4 .7-.6-.6-.2-.8 .2 .7 .6-.4 .4-.6-.6-.2 .5h-.5a.9 .9 0 0 0-.9-.8 .9 .9 0 0 0-.8 .8h-.4v-.5l-1.4-1.3h8.7l.2 .4-.2 .4 .2 .6-.2 .5 .2 .5-.2 .6 .2 .4a.65 .65 0 0 0 0 1 .65 .65 0 0 0 1-.1l.3 .2 .6-.2 .4 .2 .6-.2 .4 .2 .5-.2a.61 .61 0 0 0 .8 .3 .61 .61 0 0 0 .3-.8 .61 .61 0 0 0-.7-.4l-.3 .2-.4-.2-.6 .2-.2-.1 .2-.5-.2-.5 .2-.5-.2-.6 .2-.6-.2-.4 .8 .1 .3-.2a.6 .6 0 0 0 1.1-.1 .6 .6 0 0 0-.7-.8l-.3 .2-.6-.3-.4 .3-.6-.3-.4 .3-.6-.3-.4 .3-.6-.3-.4 .3-.1 .4h-8.7l-3.5-3.5h-5.6l-.4 .3a.48 .48 0 0 0-.5 .5 .48 .48 0 0 0 .4 .5 .48 .48 0 0 0 .6-.4l.7 1.1-.1 5.1-.4-.1-.7-.9-.7-.1v-2.6a.45 .45 0 0 0-.1-.6 .45 .45 0 0 0-.6 .1 .45 .45 0 0 0 0 .6v3.2l.8 .9-.2 1.6-.5-.1-7-7a.45 .45 0 0 0-.5-.4 .45 .45 0 0 0-.4 .5 .45 .45 0 0 0 .5 .4l7.2 7.1 1.9 .1 .3 .2-7.2 7.3-1.6-.1 .1-2.2a.59 .59 0 0 0 .6-.8 .48 .48 0 0 0 .6-.1 .48 .48 0 0 0 0-.7v-6.2a.45 .45 0 0 0-.1-.6 .45 .45 0 0 0-.6 .1 .45 .45 0 0 0 0 .6l-.1 6.5a.3 .3 0 0 1-.1 .4 .3 .3 0 0 1-.4-.2l-.1-.4-3.2-3.4a.48 .48 0 0 0 .7-.4 .48 .48 0 0 0-.6-.5l-6.1-6.2h1.4a.44 .44 0 0 0 .6 .5 .44 .44 0 0 0 .2-.8 .44 .44 0 0 0-.7 .2l-1.5 .1-2-2.1h-.4l-.2 .3h-.6l.9-.9 12.1 .1 .3-.3 .1-.6 15.9 .2a.9 .9 0 0 0 .9 .9 .9 .9 0 0 0 .9-.9h.8v.1a.9 .9 0 0 0 .9 .8 .9 .9 0 0 0 .8-1h.5l.2 .8 .6-.6 .4 .3-.7 .7 .6 .2 .8-.2-.7-.7 .4-.3 .6 .6 .2-.6-.2-.7-.6 .6-.4-.4 .7-.6-.6-.2-.8 .2 .7 .6-.4 .4-.6-.6-.2 .5h-.5a.9 .9 0 0 0-.9-.8 .9 .9 0 0 0-.8 .9h-.8v-.2a.9 .9 0 0 0-1-.7 .9 .9 0 0 0-.8 .9l-12.6-.1a.45 .45 0 0 0 .1-.6 .45 .45 0 0 0-.7-.1h-10.2a.53 .53 0 0 0-.7 .1 .53 .53 0 0 0 0 .7h-4.6l-5.4 5.3h-10.7v-6.3h15.1a.44 .44 0 0 0 .5 .4 .44 .44 0 0 0 .2-.7 .44 .44 0 0 0-.7 .2l-15.1 .1 .1-.9z"/>
<path d="M213.3 102h17.8l1.4 1.2h8.2l.7-.6 .2 .7v6l3.5 3.6 .5 .2v4.4a.46 .46 0 0 0 0 .7 .46 .46 0 0 0 .7 0 .46 .46 0 0 0 0-.7v-6.8l4.6-4.5 .1-.7h2.3l1.8 1.8 10.7 .1 .3 1.3-9.1 .1-10.7 10.7-.1 4.4-.2 .6-6.1-6.1a.49 .49 0 0 0 0-.7 .49 .49 0 0 0-.7 .1l-.1 .9-1.3-1.4 .8-.9 2.8 .1a.45 .45 0 0 0 .6-.1 .45 .45 0 0 0 0-.6 .45 .45 0 0 0-.7 0h-2.9l-1 .9-18.1-.1-5.7-5.6v-4.2a.45 .45 0 0 0-.1-.7 .45 .45 0 0 0-.6 .1 .45 .45 0 0 0 0 .6v4.4l2.8 2.8a.39 .39 0 0 1-.4 .3 .39 .39 0 0 1-.4-.4l-.4 .1-.2 .4 .2 1.6 1.2 1.3v11.1l.9 1.2h-8l.2-.5v-1.5h3.5l1.7-1.6a.46 .46 0 0 0 .4-.5 .46 .46 0 0 0-.4-.4 .46 .46 0 0 0-.5 .5l-1.4 1.4-3.4-.1v-.5l3.8-3.9 .1-19.4 6.5 6.3h21.6a.45 .45 0 0 0 .6-.2 .45 .45 0 0 0-.2-.6 .45 .45 0 0 0-.6 .2l-2.7-.1 .9-1.1v-1.2a.52 .52 0 0 0 0-.7 .52 .52 0 0 0-.7 0h-9.6l-1.9-2.1h-.6a.59 .59 0 0 0-.7-.8l-.2 .4 .2 1.4 3.1 3.2a.45 .45 0 0 0 .5 .4 .45 .45 0 0 0 .4-.5 .45 .45 0 0 0-.5-.4l-2.7-2.9 2.2 1.9h9.7l.2 .7v.4l-1.1 .8-.2 .6h-17.5l-6-6z"/>
<path d="M216.4 117.3l1.4 1.1h6.9l1.3 1.3v9.9h-9a.63 .63 0 0 0-.3-1l-.4-.5z"/>
<path d="M250.6 116l1.4-1.2v2.7a.46 .46 0 0 0 0 .7 .46 .46 0 0 0 .7 0 .46 .46 0 0 0 0-.7v-2.8l1.3-1.3h.4a1.02 1.02 0 0 0 1.6 .5 1.02 1.02 0 0 0 0-1.7 1.02 1.02 0 0 0-1.6 .6l-.3-.2 3.2-3.3 6.7 .1-.2 .4-7.1 7.2-.2 3.6a1.08 1.08 0 0 0-1-.8 1.08 1.08 0 0 0-1.1 .8 1.06 1.06 0 0 0 1 1.1 1.06 1.06 0 0 0 1.1-1l.1 1.6-.4 .5a.46 .46 0 0 0-.5 .4 .46 .46 0 0 0 .5 .5 .46 .46 0 0 0 .4-.5l.6-.7v-5.2l2-1.9 .2 .4v7.9l-.8 .1-4.9 5.1h-3.7a.76 .76 0 0 0-1.2 .5l-.5-.5v-2l-2-2a.62 .62 0 0 0 .5-1v-.8h.5l.4 .5 1.4-.1a.46 .46 0 0 0 .7-.1 .46 .46 0 0 0-.1-.6 .46 .46 0 0 0-.6 .1l-1.4-.2-.4 .4h-.5v-3.2l3.5-3.5 .2 .6v10.5a.46 .46 0 0 0 0 .6 .46 .46 0 0 0 .7 0 .46 .46 0 0 0-.1-.6v-10.5a.56 .56 0 0 0 .1-.6 .56 .56 0 0 0-.6-.3z"/>
<path d="M242.3 106.5a.6 .6 0 0 0 .7-.6l.5-.5 .4 .2 6.3 .1-4.5 4.7-.2 1.8-3.2-3.2z"/>
<path d="M256 104.5h6.3l.1 .7 1.5 1.4h-8.5a1.27 1.27 0 0 0 .6-2.1z"/>
<path d="M255.8 101.5h1.7a.51 .51 0 0 0 0 .7 .51 .51 0 0 0 .7 0 .51 .51 0 0 0 .1-.7l4.1-.1 3.3-3.1 .1 .7 .6 .8h-1.5l-1.6 1.7a.62 .62 0 0 0 .2 1l-1.7 .1a.46 .46 0 0 0-.6 0 .46 .46 0 0 0 0 .6 .46 .46 0 0 0 .6 0l4.8 .2-.7 .5h-9.3l.1-1.1-.2-.6-.6 .6-.3-.4 .5-.6z"/>
<path d="M200.7 95l.7-.6 .4 .3-.6 .6 .3 .3-.3 .2 .6 .6-.4 .4-.8-.7z"/>
<path d="M200.7 89l.7-.6 .4 .3-.6 .6 .3 .3-.3 .2 .6 .6-.4 .4-.8-.7z"/>
<path d="M202.3 88.7l.4-.3 .6 .6v1.2l-.6 .6-.4-.4 .6-.6-.3-.2 .3-.3z"/>
<path d="M273.6 87.5l.7-.6 .4 .3-.6 .6 .3 .3-.3 .2 .6 .6-.4 .4-.8-.7z"/>
<path d="M275.2 87.2l.4-.3 .6 .5h.3v1.4l-.3-.1-.6 .6-.4-.4 .6-.6-.3-.2 .3-.3z"/>
<path d="M200.7 86.8l.4-.1 .7 .7-.4 .4-.8-.7z"/>
</g>
</svg>
